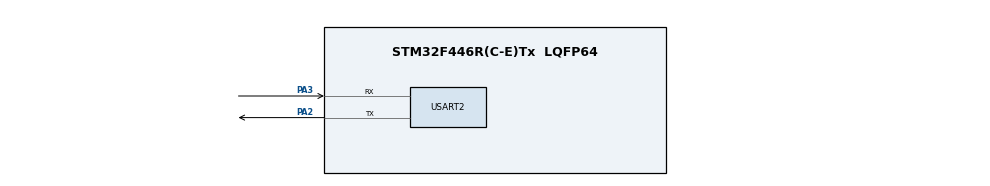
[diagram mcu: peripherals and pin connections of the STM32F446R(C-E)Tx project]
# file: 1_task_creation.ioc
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FREERTOS.Tasks01=defaultTask,24,128,StartDefaultTask,Default,NULL,Dynamic,NULL,NULL
Mcu.Family=STM32F4
Mcu.Name=STM32F446R(C-E)Tx
Mcu.Package=LQFP64
NVIC.PriorityGroup=NVIC_PRIORITYGROUP_4
NVIC.TIM1_UP_TIM10_IRQn=true\:15\:0\:false\:false\:true\:false\:false\:true\:true
NVIC.TimeBase=TIM1_UP_TIM10_IRQn
NVIC.TimeBaseIP=TIM1
PA2.Mode=Asynchronous
PA2.Signal=USART2_TX
PA3.Mode=Asynchronous
PA3.Signal=USART2_RX
ProjectManager.HeapSize=0x200
ProjectManager.StackSize=0x400
ProjectManager.TargetToolchain=STM32CubeIDE
RCC.AHBFreq_Value=84000000
RCC.APB1CLKDivider=RCC_HCLK_DIV2
RCC.APB1Freq_Value=42000000
RCC.APB1TimFreq_Value=84000000
RCC.APB2Freq_Value=84000000
RCC.APB2TimFreq_Value=84000000
RCC.CortexFreq_Value=84000000
RCC.FLatency-AdvancedSettings=FLASH_LATENCY_2
RCC.HCLKFreq_Value=84000000
RCC.HSE_VALUE=8000000
RCC.HSI_VALUE=16000000
RCC.LSE_VALUE=32768
RCC.PLLN=336
RCC.PLLP=RCC_PLLP_DIV4
RCC.SYSCLKFreq_VALUE=84000000
RCC.SYSCLKSource=RCC_SYSCLKSOURCE_PLLCLK
RCC.USBFreq_Value=168000000
RCC.VCOOutputFreq_Value=336000000
USART2.VirtualMode=VM_ASYNC
VP_FREERTOS_VS_CMSIS_V2.Mode=CMSIS_V2
VP_SYS_VS_tim1.Mode=TIM1
board=NUCLEO-F446RE

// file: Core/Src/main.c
#include "main.h"
#include "cmsis_os.h"
#include "stdio.h"
#include <stdlib.h>
#include "data_packet.h"

// Sensors
#include "tmp36.h"
#include "adxl345.h"
#include "ky039.h"

UART_HandleTypeDef huart2;

void SystemClock_Config(void);
static void MX_GPIO_Init(void);
static void MX_USART2_UART_Init(void);

// Initialize data packets with sensor source
static Data_t xStructToSend[3] =
{
    { .sDataSource = temperature_sensor },
    { .sDataSource = heartbeat_sensor },
    { .sDataSource = accelerometer_sensor }
};

TaskHandle_t receiver_handle, temp_task_handle, heart_task_handle, accel_task_handle;

QueueHandle_t xTempQueue;
QueueHandle_t xHeartQueue;
QueueHandle_t xAccelQueue;

QueueSetHandle_t xQueueSet;

void queue_setup();
void ReceiverTask(void *pvParameters);
void SenderTask(void *pvParameters);

int main(void)
{
	HAL_Init();
	SystemClock_Config();
	MX_GPIO_Init();
	MX_USART2_UART_Init();

	I2C1_init();
	ADC1_DMA2_init();

	adxl_init();		// adxl345
	start_conversion();	// tmp36 + ky039

	queue_setup();

	xTaskCreate(ReceiverTask, "Receiver Task", 100, NULL, 1, &receiver_handle);

	// Pass in pointer to structs with just the sDataSource info
	xTaskCreate(SenderTask, "Temperature Sender Task", 100, (void *)&(xStructToSend[0]),
	2, &temp_task_handle);

	xTaskCreate(SenderTask, "Heartbeat Sender Task", 100, (void *)&(xStructToSend[1]),
	2, &heart_task_handle);

	xTaskCreate(SenderTask, "Accelerometer Sender Task", 100, (void *)&(xStructToSend[2]),
	2, &accel_task_handle);

	vTaskStartScheduler();

	while (1) {}

}

void queue_setup()
{
	// Create queues per sensor
	xTempQueue = xQueueCreate(1, sizeof(Data_t));
	xHeartQueue = xQueueCreate(1, sizeof(Data_t));
	xAccelQueue = xQueueCreate(1, sizeof(Data_t));

	xQueueSet = xQueueCreateSet(3 * 1); // # queues x # length per queue

	xQueueAddToSet(xTempQueue, xQueueSet);
	xQueueAddToSet(xHeartQueue, xQueueSet);
	xQueueAddToSet(xAccelQueue, xQueueSet);
}

int uart2_write(int ch)
{
	// Check that TXE is empty
	while(!(USART2->SR & USART_SR_TXE)){}

	// Write to TXE
	USART2->DR = (ch & 0xFF);
	return ch;
}

int __io_putchar(int ch)
{
	uart2_write(ch);
	return ch;
}

void SenderTask(void *pvParameters)
{
	BaseType_t qState;
	Data_t *pPacket = pvParameters;
	TickType_t sampleDelay;

	while(1)
	{
		// Populates values and sends to corresponding queue based on which sensor task uses function
		switch(pPacket->sDataSource)
		{
			case temperature_sensor:
				pPacket->payload.temp.tempValue = read_tmp();
				qState = xQueueOverwrite(xTempQueue, pPacket);
				sampleDelay = 1000; // 1 second
				break;
			case heartbeat_sensor:
				int possible_bpm = read_heart();  // Make sure new reading is available
				if (possible_bpm != -1) pPacket->payload.heart.bpmValue = possible_bpm;
				qState = xQueueOverwrite(xHeartQueue, pPacket);
				sampleDelay = 20; // 20 ms
				break;
			case accelerometer_sensor:
				pPacket->payload.accel.vectorMag = read_accel();
				qState = xQueueOverwrite(xAccelQueue, pPacket);
				sampleDelay = 100; // 100 ms
				break;
			default:
				printf("Error: Invalid sensor source.");
				sampleDelay = 500;
				break;
		}

		if(qState != pdPASS)
		{
			printf("Error: Send failed for %d\r\n", pPacket->sDataSource);
		}

		vTaskDelay(pdMS_TO_TICKS(sampleDelay));
	}
}

void ReceiverTask(void *pvParameters)
{
    QueueSetMemberHandle_t xActivatedQueue;
    Data_t rxData;

    while (1)
    {
        // Block until any queue in the set has data ready
        xActivatedQueue = xQueueSelectFromSet(xQueueSet, portMAX_DELAY);

        if (xActivatedQueue == xTempQueue)
        {
            xQueueReceive(xTempQueue, &rxData, portMAX_DELAY);
            int32_t tempC_x10 = rxData.payload.temp.tempValue;
			int32_t tempC_whole = tempC_x10 / 10;
			int32_t tempC_tenths = abs(tempC_x10 % 10);
			printf("Temperature: %ld.%ld C\n\r", tempC_whole, tempC_tenths);
        }
        else if (xActivatedQueue == xHeartQueue)
        {
            xQueueReceive(xHeartQueue, &rxData, portMAX_DELAY);
            int32_t bpm = rxData.payload.heart.bpmValue;
            if (bpm > 100 || bpm < 60) printf("ALERT! | Abnormal Heartbeat!");
            printf("Heartbeat = %ld BPM\r\n", bpm);
        }
        else if (xActivatedQueue == xAccelQueue)
        {
            xQueueReceive(xAccelQueue, &rxData, portMAX_DELAY);
            int32_t vectorMag_x10 = rxData.payload.accel.vectorMag;
            int32_t vectorMag_whole = vectorMag_x10 / 100;
            int32_t vectorMag_decimal = abs(vectorMag_x10 % 100);
            printf("Movement (vector magnitude): %ld.%ld m/s^2\n\r", vectorMag_whole, vectorMag_decimal);
        }
    }
}

// <----------------------------------------------- GENERATED | DO NOT EDIT --------------------------------------------->

void SystemClock_Config(void)
{
  RCC_OscInitTypeDef RCC_OscInitStruct = {0};
  RCC_ClkInitTypeDef RCC_ClkInitStruct = {0};

  /** Configure the main internal regulator output voltage
  */
  __HAL_RCC_PWR_CLK_ENABLE();
  __HAL_PWR_VOLTAGESCALING_CONFIG(PWR_REGULATOR_VOLTAGE_SCALE1);
  /** Initializes the RCC Oscillators according to the specified parameters
  * in the RCC_OscInitTypeDef structure.
  */
  RCC_OscInitStruct.OscillatorType = RCC_OSCILLATORTYPE_HSI;
  RCC_OscInitStruct.HSIState = RCC_HSI_ON;
  RCC_OscInitStruct.HSICalibrationValue = RCC_HSICALIBRATION_DEFAULT;
  RCC_OscInitStruct.PLL.PLLState = RCC_PLL_NONE;
  if (HAL_RCC_OscConfig(&RCC_OscInitStruct) != HAL_OK)
  {
    Error_Handler();
  }
  /** Initializes the CPU, AHB and APB buses clocks
  */
  RCC_ClkInitStruct.ClockType = RCC_CLOCKTYPE_HCLK|RCC_CLOCKTYPE_SYSCLK
                              |RCC_CLOCKTYPE_PCLK1|RCC_CLOCKTYPE_PCLK2;
  RCC_ClkInitStruct.SYSCLKSource = RCC_SYSCLKSOURCE_HSI;
  RCC_ClkInitStruct.AHBCLKDivider = RCC_SYSCLK_DIV1;
  RCC_ClkInitStruct.APB1CLKDivider = RCC_HCLK_DIV1;
  RCC_ClkInitStruct.APB2CLKDivider = RCC_HCLK_DIV1;

  if (HAL_RCC_ClockConfig(&RCC_ClkInitStruct, FLASH_LATENCY_0) != HAL_OK)
  {
    Error_Handler();
  }
}

static void MX_USART2_UART_Init(void)
{

  huart2.Instance = USART2;
  huart2.Init.BaudRate = 115200;
  huart2.Init.WordLength = UART_WORDLENGTH_8B;
  huart2.Init.StopBits = UART_STOPBITS_1;
  huart2.Init.Parity = UART_PARITY_NONE;
  huart2.Init.Mode = UART_MODE_TX_RX;
  huart2.Init.HwFlowCtl = UART_HWCONTROL_NONE;
  huart2.Init.OverSampling = UART_OVERSAMPLING_16;
  if (HAL_UART_Init(&huart2) != HAL_OK)
  {
    Error_Handler();
  }

}

static void MX_GPIO_Init(void)
{

  /* GPIO Ports Clock Enable */
  __HAL_RCC_GPIOA_CLK_ENABLE();

}

void HAL_TIM_PeriodElapsedCallback(TIM_HandleTypeDef *htim)
{
  if (htim->Instance == TIM11) {
    HAL_IncTick();
  }
}

void Error_Handler(void)
{
  __disable_irq();
  while (1)
  {
  }
}
